VERSION 5.7 ;
  NOWIREEXTENSIONATPIN ON ;
  DIVIDERCHAR "/" ;
  BUSBITCHARS "[]" ;
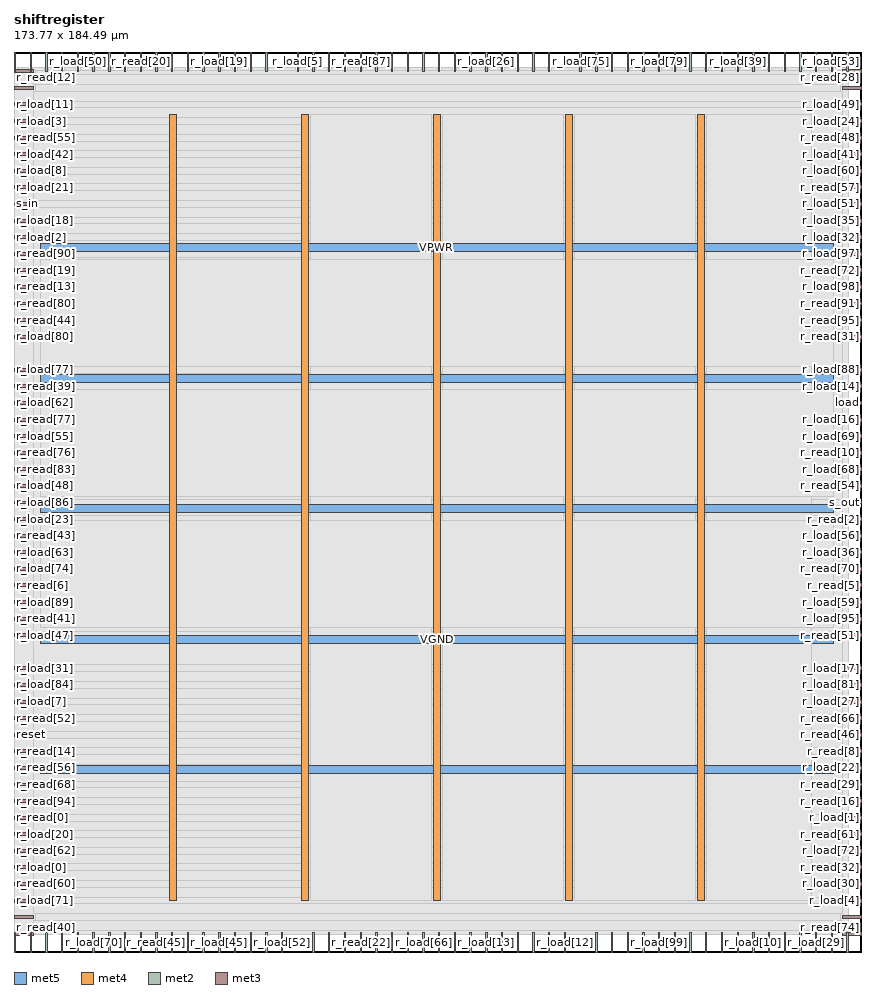
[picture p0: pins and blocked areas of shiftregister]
MACRO shiftregister
  CLASS BLOCK ;
  FOREIGN shiftregister ;
  ORIGIN 0.000 0.000 ;
  SIZE 173.770 BY 184.490 ;
  PIN VGND
    DIRECTION INPUT ;
    USE GROUND ;
    PORT
      LAYER met5 ;
        RECT 5.520 63.335 167.900 64.935 ;
    END
    PORT
      LAYER met5 ;
        RECT 5.520 116.825 167.900 118.425 ;
    END
    PORT
      LAYER met4 ;
        RECT 58.850 10.640 60.450 171.600 ;
    END
    PORT
      LAYER met4 ;
        RECT 112.975 10.640 114.575 171.600 ;
    END
  END VGND
  PIN VPWR
    DIRECTION INPUT ;
    USE POWER ;
    PORT
      LAYER met5 ;
        RECT 5.520 36.585 167.900 38.185 ;
    END
    PORT
      LAYER met5 ;
        RECT 5.520 90.080 167.900 91.680 ;
    END
    PORT
      LAYER met5 ;
        RECT 5.520 143.575 167.900 145.175 ;
    END
    PORT
      LAYER met4 ;
        RECT 31.780 10.640 33.380 171.600 ;
    END
    PORT
      LAYER met4 ;
        RECT 85.910 10.640 87.510 171.600 ;
    END
    PORT
      LAYER met4 ;
        RECT 140.035 10.640 141.635 171.600 ;
    END
  END VPWR
  PIN clk
    DIRECTION INPUT ;
    USE SIGNAL ;
    PORT
      LAYER met2 ;
        RECT 125.670 180.490 125.950 184.490 ;
    END
  END clk
  PIN load
    DIRECTION INPUT ;
    USE SIGNAL ;
    PORT
      LAYER met3 ;
        RECT 169.770 112.240 173.770 112.840 ;
    END
  END load
  PIN r_load[0]
    DIRECTION OUTPUT TRISTATE ;
    USE SIGNAL ;
    PORT
      LAYER met3 ;
        RECT 0.000 17.040 4.000 17.640 ;
    END
  END r_load[0]
  PIN r_load[10]
    DIRECTION OUTPUT TRISTATE ;
    USE SIGNAL ;
    PORT
      LAYER met2 ;
        RECT 151.430 0.000 151.710 4.000 ;
    END
  END r_load[10]
  PIN r_load[11]
    DIRECTION OUTPUT TRISTATE ;
    USE SIGNAL ;
    PORT
      LAYER met3 ;
        RECT 0.000 173.440 4.000 174.040 ;
    END
  END r_load[11]
  PIN r_load[12]
    DIRECTION OUTPUT TRISTATE ;
    USE SIGNAL ;
    PORT
      LAYER met2 ;
        RECT 112.790 0.000 113.070 4.000 ;
    END
  END r_load[12]
  PIN r_load[13]
    DIRECTION OUTPUT TRISTATE ;
    USE SIGNAL ;
    PORT
      LAYER met2 ;
        RECT 96.690 0.000 96.970 4.000 ;
    END
  END r_load[13]
  PIN r_load[14]
    DIRECTION OUTPUT TRISTATE ;
    USE SIGNAL ;
    PORT
      LAYER met3 ;
        RECT 169.770 115.640 173.770 116.240 ;
    END
  END r_load[14]
  PIN r_load[15]
    DIRECTION OUTPUT TRISTATE ;
    USE SIGNAL ;
    PORT
      LAYER met2 ;
        RECT 38.730 180.490 39.010 184.490 ;
    END
  END r_load[15]
  PIN r_load[16]
    DIRECTION OUTPUT TRISTATE ;
    USE SIGNAL ;
    PORT
      LAYER met3 ;
        RECT 169.770 108.840 173.770 109.440 ;
    END
  END r_load[16]
  PIN r_load[17]
    DIRECTION OUTPUT TRISTATE ;
    USE SIGNAL ;
    PORT
      LAYER met3 ;
        RECT 169.770 57.840 173.770 58.440 ;
    END
  END r_load[17]
  PIN r_load[18]
    DIRECTION OUTPUT TRISTATE ;
    USE SIGNAL ;
    PORT
      LAYER met3 ;
        RECT 0.000 149.640 4.000 150.240 ;
    END
  END r_load[18]
  PIN r_load[19]
    DIRECTION OUTPUT TRISTATE ;
    USE SIGNAL ;
    PORT
      LAYER met2 ;
        RECT 41.950 180.490 42.230 184.490 ;
    END
  END r_load[19]
  PIN r_load[1]
    DIRECTION OUTPUT TRISTATE ;
    USE SIGNAL ;
    PORT
      LAYER met3 ;
        RECT 169.770 27.240 173.770 27.840 ;
    END
  END r_load[1]
  PIN r_load[20]
    DIRECTION OUTPUT TRISTATE ;
    USE SIGNAL ;
    PORT
      LAYER met3 ;
        RECT 0.000 23.840 4.000 24.440 ;
    END
  END r_load[20]
  PIN r_load[21]
    DIRECTION OUTPUT TRISTATE ;
    USE SIGNAL ;
    PORT
      LAYER met3 ;
        RECT 0.000 156.440 4.000 157.040 ;
    END
  END r_load[21]
  PIN r_load[22]
    DIRECTION OUTPUT TRISTATE ;
    USE SIGNAL ;
    PORT
      LAYER met3 ;
        RECT 169.770 37.440 173.770 38.040 ;
    END
  END r_load[22]
  PIN r_load[23]
    DIRECTION OUTPUT TRISTATE ;
    USE SIGNAL ;
    PORT
      LAYER met3 ;
        RECT 0.000 88.440 4.000 89.040 ;
    END
  END r_load[23]
  PIN r_load[24]
    DIRECTION OUTPUT TRISTATE ;
    USE SIGNAL ;
    PORT
      LAYER met3 ;
        RECT 169.770 170.040 173.770 170.640 ;
    END
  END r_load[24]
  PIN r_load[25]
    DIRECTION OUTPUT TRISTATE ;
    USE SIGNAL ;
    PORT
      LAYER met2 ;
        RECT 138.550 180.490 138.830 184.490 ;
    END
  END r_load[25]
  PIN r_load[26]
    DIRECTION OUTPUT TRISTATE ;
    USE SIGNAL ;
    PORT
      LAYER met2 ;
        RECT 96.690 180.490 96.970 184.490 ;
    END
  END r_load[26]
  PIN r_load[27]
    DIRECTION OUTPUT TRISTATE ;
    USE SIGNAL ;
    PORT
      LAYER met3 ;
        RECT 169.770 51.040 173.770 51.640 ;
    END
  END r_load[27]
  PIN r_load[28]
    DIRECTION OUTPUT TRISTATE ;
    USE SIGNAL ;
    PORT
      LAYER met2 ;
        RECT 67.710 180.490 67.990 184.490 ;
    END
  END r_load[28]
  PIN r_load[29]
    DIRECTION OUTPUT TRISTATE ;
    USE SIGNAL ;
    PORT
      LAYER met2 ;
        RECT 164.310 0.000 164.590 4.000 ;
    END
  END r_load[29]
  PIN r_load[2]
    DIRECTION OUTPUT TRISTATE ;
    USE SIGNAL ;
    PORT
      LAYER met3 ;
        RECT 0.000 146.240 4.000 146.840 ;
    END
  END r_load[2]
  PIN r_load[30]
    DIRECTION OUTPUT TRISTATE ;
    USE SIGNAL ;
    PORT
      LAYER met3 ;
        RECT 169.770 13.640 173.770 14.240 ;
    END
  END r_load[30]
  PIN r_load[31]
    DIRECTION OUTPUT TRISTATE ;
    USE SIGNAL ;
    PORT
      LAYER met3 ;
        RECT 0.000 57.840 4.000 58.440 ;
    END
  END r_load[31]
  PIN r_load[32]
    DIRECTION OUTPUT TRISTATE ;
    USE SIGNAL ;
    PORT
      LAYER met3 ;
        RECT 169.770 146.240 173.770 146.840 ;
    END
  END r_load[32]
  PIN r_load[33]
    DIRECTION OUTPUT TRISTATE ;
    USE SIGNAL ;
    PORT
      LAYER met2 ;
        RECT 51.610 0.000 51.890 4.000 ;
    END
  END r_load[33]
  PIN r_load[34]
    DIRECTION OUTPUT TRISTATE ;
    USE SIGNAL ;
    PORT
      LAYER met2 ;
        RECT 87.030 0.000 87.310 4.000 ;
    END
  END r_load[34]
  PIN r_load[35]
    DIRECTION OUTPUT TRISTATE ;
    USE SIGNAL ;
    PORT
      LAYER met3 ;
        RECT 169.770 149.640 173.770 150.240 ;
    END
  END r_load[35]
  PIN r_load[36]
    DIRECTION OUTPUT TRISTATE ;
    USE SIGNAL ;
    PORT
      LAYER met3 ;
        RECT 169.770 81.640 173.770 82.240 ;
    END
  END r_load[36]
  PIN r_load[37]
    DIRECTION OUTPUT TRISTATE ;
    USE SIGNAL ;
    PORT
      LAYER met2 ;
        RECT 141.770 0.000 142.050 4.000 ;
    END
  END r_load[37]
  PIN r_load[38]
    DIRECTION OUTPUT TRISTATE ;
    USE SIGNAL ;
    PORT
      LAYER met2 ;
        RECT 122.450 0.000 122.730 4.000 ;
    END
  END r_load[38]
  PIN r_load[39]
    DIRECTION OUTPUT TRISTATE ;
    USE SIGNAL ;
    PORT
      LAYER met2 ;
        RECT 148.210 180.490 148.490 184.490 ;
    END
  END r_load[39]
  PIN r_load[3]
    DIRECTION OUTPUT TRISTATE ;
    USE SIGNAL ;
    PORT
      LAYER met3 ;
        RECT 0.000 170.040 4.000 170.640 ;
    END
  END r_load[3]
  PIN r_load[40]
    DIRECTION OUTPUT TRISTATE ;
    USE SIGNAL ;
    PORT
      LAYER met2 ;
        RECT 35.510 180.490 35.790 184.490 ;
    END
  END r_load[40]
  PIN r_load[41]
    DIRECTION OUTPUT TRISTATE ;
    USE SIGNAL ;
    PORT
      LAYER met3 ;
        RECT 169.770 163.240 173.770 163.840 ;
    END
  END r_load[41]
  PIN r_load[42]
    DIRECTION OUTPUT TRISTATE ;
    USE SIGNAL ;
    PORT
      LAYER met3 ;
        RECT 0.000 163.240 4.000 163.840 ;
    END
  END r_load[42]
  PIN r_load[43]
    DIRECTION OUTPUT TRISTATE ;
    USE SIGNAL ;
    PORT
      LAYER met2 ;
        RECT 48.390 180.490 48.670 184.490 ;
    END
  END r_load[43]
  PIN r_load[44]
    DIRECTION OUTPUT TRISTATE ;
    USE SIGNAL ;
    PORT
      LAYER met2 ;
        RECT 170.750 0.000 171.030 4.000 ;
    END
  END r_load[44]
  PIN r_load[45]
    DIRECTION OUTPUT TRISTATE ;
    USE SIGNAL ;
    PORT
      LAYER met2 ;
        RECT 41.950 0.000 42.230 4.000 ;
    END
  END r_load[45]
  PIN r_load[46]
    DIRECTION OUTPUT TRISTATE ;
    USE SIGNAL ;
    PORT
      LAYER met2 ;
        RECT 157.870 180.490 158.150 184.490 ;
    END
  END r_load[46]
  PIN r_load[47]
    DIRECTION OUTPUT TRISTATE ;
    USE SIGNAL ;
    PORT
      LAYER met3 ;
        RECT 0.000 64.640 4.000 65.240 ;
    END
  END r_load[47]
  PIN r_load[48]
    DIRECTION OUTPUT TRISTATE ;
    USE SIGNAL ;
    PORT
      LAYER met3 ;
        RECT 0.000 95.240 4.000 95.840 ;
    END
  END r_load[48]
  PIN r_load[49]
    DIRECTION OUTPUT TRISTATE ;
    USE SIGNAL ;
    PORT
      LAYER met3 ;
        RECT 169.770 173.440 173.770 174.040 ;
    END
  END r_load[49]
  PIN r_load[4]
    DIRECTION OUTPUT TRISTATE ;
    USE SIGNAL ;
    PORT
      LAYER met3 ;
        RECT 169.770 10.240 173.770 10.840 ;
    END
  END r_load[4]
  PIN r_load[50]
    DIRECTION OUTPUT TRISTATE ;
    USE SIGNAL ;
    PORT
      LAYER met2 ;
        RECT 12.970 180.490 13.250 184.490 ;
    END
  END r_load[50]
  PIN r_load[51]
    DIRECTION OUTPUT TRISTATE ;
    USE SIGNAL ;
    PORT
      LAYER met3 ;
        RECT 169.770 153.040 173.770 153.640 ;
    END
  END r_load[51]
  PIN r_load[52]
    DIRECTION OUTPUT TRISTATE ;
    USE SIGNAL ;
    PORT
      LAYER met2 ;
        RECT 54.830 0.000 55.110 4.000 ;
    END
  END r_load[52]
  PIN r_load[53]
    DIRECTION OUTPUT TRISTATE ;
    USE SIGNAL ;
    PORT
      LAYER met2 ;
        RECT 170.750 180.490 171.030 184.490 ;
    END
  END r_load[53]
  PIN r_load[54]
    DIRECTION OUTPUT TRISTATE ;
    USE SIGNAL ;
    PORT
      LAYER met2 ;
        RECT 161.090 180.490 161.370 184.490 ;
    END
  END r_load[54]
  PIN r_load[55]
    DIRECTION OUTPUT TRISTATE ;
    USE SIGNAL ;
    PORT
      LAYER met3 ;
        RECT 0.000 105.440 4.000 106.040 ;
    END
  END r_load[55]
  PIN r_load[56]
    DIRECTION OUTPUT TRISTATE ;
    USE SIGNAL ;
    PORT
      LAYER met3 ;
        RECT 169.770 85.040 173.770 85.640 ;
    END
  END r_load[56]
  PIN r_load[57]
    DIRECTION OUTPUT TRISTATE ;
    USE SIGNAL ;
    PORT
      LAYER met2 ;
        RECT 144.990 0.000 145.270 4.000 ;
    END
  END r_load[57]
  PIN r_load[58]
    DIRECTION OUTPUT TRISTATE ;
    USE SIGNAL ;
    PORT
      LAYER met2 ;
        RECT 90.250 180.490 90.530 184.490 ;
    END
  END r_load[58]
  PIN r_load[59]
    DIRECTION OUTPUT TRISTATE ;
    USE SIGNAL ;
    PORT
      LAYER met3 ;
        RECT 169.770 71.440 173.770 72.040 ;
    END
  END r_load[59]
  PIN r_load[5]
    DIRECTION OUTPUT TRISTATE ;
    USE SIGNAL ;
    PORT
      LAYER met2 ;
        RECT 58.050 180.490 58.330 184.490 ;
    END
  END r_load[5]
  PIN r_load[60]
    DIRECTION OUTPUT TRISTATE ;
    USE SIGNAL ;
    PORT
      LAYER met3 ;
        RECT 169.770 159.840 173.770 160.440 ;
    END
  END r_load[60]
  PIN r_load[61]
    DIRECTION OUTPUT TRISTATE ;
    USE SIGNAL ;
    PORT
      LAYER met2 ;
        RECT 141.770 180.490 142.050 184.490 ;
    END
  END r_load[61]
  PIN r_load[62]
    DIRECTION OUTPUT TRISTATE ;
    USE SIGNAL ;
    PORT
      LAYER met3 ;
        RECT 0.000 112.240 4.000 112.840 ;
    END
  END r_load[62]
  PIN r_load[63]
    DIRECTION OUTPUT TRISTATE ;
    USE SIGNAL ;
    PORT
      LAYER met3 ;
        RECT 0.000 81.640 4.000 82.240 ;
    END
  END r_load[63]
  PIN r_load[64]
    DIRECTION OUTPUT TRISTATE ;
    USE SIGNAL ;
    PORT
      LAYER met2 ;
        RECT 32.290 180.490 32.570 184.490 ;
    END
  END r_load[64]
  PIN r_load[65]
    DIRECTION OUTPUT TRISTATE ;
    USE SIGNAL ;
    PORT
      LAYER met2 ;
        RECT 77.370 180.490 77.650 184.490 ;
    END
  END r_load[65]
  PIN r_load[66]
    DIRECTION OUTPUT TRISTATE ;
    USE SIGNAL ;
    PORT
      LAYER met2 ;
        RECT 83.810 0.000 84.090 4.000 ;
    END
  END r_load[66]
  PIN r_load[67]
    DIRECTION OUTPUT TRISTATE ;
    USE SIGNAL ;
    PORT
      LAYER met2 ;
        RECT 167.530 0.000 167.810 4.000 ;
    END
  END r_load[67]
  PIN r_load[68]
    DIRECTION OUTPUT TRISTATE ;
    USE SIGNAL ;
    PORT
      LAYER met3 ;
        RECT 169.770 98.640 173.770 99.240 ;
    END
  END r_load[68]
  PIN r_load[69]
    DIRECTION OUTPUT TRISTATE ;
    USE SIGNAL ;
    PORT
      LAYER met3 ;
        RECT 169.770 105.440 173.770 106.040 ;
    END
  END r_load[69]
  PIN r_load[6]
    DIRECTION OUTPUT TRISTATE ;
    USE SIGNAL ;
    PORT
      LAYER met2 ;
        RECT 45.170 180.490 45.450 184.490 ;
    END
  END r_load[6]
  PIN r_load[70]
    DIRECTION OUTPUT TRISTATE ;
    USE SIGNAL ;
    PORT
      LAYER met2 ;
        RECT 16.190 0.000 16.470 4.000 ;
    END
  END r_load[70]
  PIN r_load[71]
    DIRECTION OUTPUT TRISTATE ;
    USE SIGNAL ;
    PORT
      LAYER met3 ;
        RECT 0.000 10.240 4.000 10.840 ;
    END
  END r_load[71]
  PIN r_load[72]
    DIRECTION OUTPUT TRISTATE ;
    USE SIGNAL ;
    PORT
      LAYER met3 ;
        RECT 169.770 20.440 173.770 21.040 ;
    END
  END r_load[72]
  PIN r_load[73]
    DIRECTION OUTPUT TRISTATE ;
    USE SIGNAL ;
    PORT
      LAYER met2 ;
        RECT 61.270 180.490 61.550 184.490 ;
    END
  END r_load[73]
  PIN r_load[74]
    DIRECTION OUTPUT TRISTATE ;
    USE SIGNAL ;
    PORT
      LAYER met3 ;
        RECT 0.000 78.240 4.000 78.840 ;
    END
  END r_load[74]
  PIN r_load[75]
    DIRECTION OUTPUT TRISTATE ;
    USE SIGNAL ;
    PORT
      LAYER met2 ;
        RECT 116.010 180.490 116.290 184.490 ;
    END
  END r_load[75]
  PIN r_load[76]
    DIRECTION OUTPUT TRISTATE ;
    USE SIGNAL ;
    PORT
      LAYER met2 ;
        RECT 138.550 0.000 138.830 4.000 ;
    END
  END r_load[76]
  PIN r_load[77]
    DIRECTION OUTPUT TRISTATE ;
    USE SIGNAL ;
    PORT
      LAYER met3 ;
        RECT 0.000 119.040 4.000 119.640 ;
    END
  END r_load[77]
  PIN r_load[78]
    DIRECTION OUTPUT TRISTATE ;
    USE SIGNAL ;
    PORT
      LAYER met2 ;
        RECT 128.890 180.490 129.170 184.490 ;
    END
  END r_load[78]
  PIN r_load[79]
    DIRECTION OUTPUT TRISTATE ;
    USE SIGNAL ;
    PORT
      LAYER met2 ;
        RECT 132.110 180.490 132.390 184.490 ;
    END
  END r_load[79]
  PIN r_load[7]
    DIRECTION OUTPUT TRISTATE ;
    USE SIGNAL ;
    PORT
      LAYER met3 ;
        RECT 0.000 51.040 4.000 51.640 ;
    END
  END r_load[7]
  PIN r_load[80]
    DIRECTION OUTPUT TRISTATE ;
    USE SIGNAL ;
    PORT
      LAYER met3 ;
        RECT 0.000 125.840 4.000 126.440 ;
    END
  END r_load[80]
  PIN r_load[81]
    DIRECTION OUTPUT TRISTATE ;
    USE SIGNAL ;
    PORT
      LAYER met3 ;
        RECT 169.770 54.440 173.770 55.040 ;
    END
  END r_load[81]
  PIN r_load[82]
    DIRECTION OUTPUT TRISTATE ;
    USE SIGNAL ;
    PORT
      LAYER met2 ;
        RECT 148.210 0.000 148.490 4.000 ;
    END
  END r_load[82]
  PIN r_load[83]
    DIRECTION OUTPUT TRISTATE ;
    USE SIGNAL ;
    PORT
      LAYER met3 ;
        RECT 0.000 6.840 4.000 7.440 ;
    END
  END r_load[83]
  PIN r_load[84]
    DIRECTION OUTPUT TRISTATE ;
    USE SIGNAL ;
    PORT
      LAYER met3 ;
        RECT 0.000 54.440 4.000 55.040 ;
    END
  END r_load[84]
  PIN r_load[85]
    DIRECTION OUTPUT TRISTATE ;
    USE SIGNAL ;
    PORT
      LAYER met2 ;
        RECT 109.570 0.000 109.850 4.000 ;
    END
  END r_load[85]
  PIN r_load[86]
    DIRECTION OUTPUT TRISTATE ;
    USE SIGNAL ;
    PORT
      LAYER met3 ;
        RECT 0.000 91.840 4.000 92.440 ;
    END
  END r_load[86]
  PIN r_load[87]
    DIRECTION OUTPUT TRISTATE ;
    USE SIGNAL ;
    PORT
      LAYER met2 ;
        RECT 93.470 0.000 93.750 4.000 ;
    END
  END r_load[87]
  PIN r_load[88]
    DIRECTION OUTPUT TRISTATE ;
    USE SIGNAL ;
    PORT
      LAYER met3 ;
        RECT 169.770 119.040 173.770 119.640 ;
    END
  END r_load[88]
  PIN r_load[89]
    DIRECTION OUTPUT TRISTATE ;
    USE SIGNAL ;
    PORT
      LAYER met3 ;
        RECT 0.000 71.440 4.000 72.040 ;
    END
  END r_load[89]
  PIN r_load[8]
    DIRECTION OUTPUT TRISTATE ;
    USE SIGNAL ;
    PORT
      LAYER met3 ;
        RECT 0.000 159.840 4.000 160.440 ;
    END
  END r_load[8]
  PIN r_load[90]
    DIRECTION OUTPUT TRISTATE ;
    USE SIGNAL ;
    PORT
      LAYER met2 ;
        RECT 61.270 0.000 61.550 4.000 ;
    END
  END r_load[90]
  PIN r_load[91]
    DIRECTION OUTPUT TRISTATE ;
    USE SIGNAL ;
    PORT
      LAYER met3 ;
        RECT 169.770 6.840 173.770 7.440 ;
    END
  END r_load[91]
  PIN r_load[92]
    DIRECTION OUTPUT TRISTATE ;
    USE SIGNAL ;
    PORT
      LAYER met2 ;
        RECT 25.850 0.000 26.130 4.000 ;
    END
  END r_load[92]
  PIN r_load[93]
    DIRECTION OUTPUT TRISTATE ;
    USE SIGNAL ;
    PORT
      LAYER met2 ;
        RECT 87.030 180.490 87.310 184.490 ;
    END
  END r_load[93]
  PIN r_load[94]
    DIRECTION OUTPUT TRISTATE ;
    USE SIGNAL ;
    PORT
      LAYER met2 ;
        RECT 167.530 180.490 167.810 184.490 ;
    END
  END r_load[94]
  PIN r_load[95]
    DIRECTION OUTPUT TRISTATE ;
    USE SIGNAL ;
    PORT
      LAYER met3 ;
        RECT 169.770 68.040 173.770 68.640 ;
    END
  END r_load[95]
  PIN r_load[96]
    DIRECTION OUTPUT TRISTATE ;
    USE SIGNAL ;
    PORT
      LAYER met2 ;
        RECT 144.990 180.490 145.270 184.490 ;
    END
  END r_load[96]
  PIN r_load[97]
    DIRECTION OUTPUT TRISTATE ;
    USE SIGNAL ;
    PORT
      LAYER met3 ;
        RECT 169.770 142.840 173.770 143.440 ;
    END
  END r_load[97]
  PIN r_load[98]
    DIRECTION OUTPUT TRISTATE ;
    USE SIGNAL ;
    PORT
      LAYER met3 ;
        RECT 169.770 136.040 173.770 136.640 ;
    END
  END r_load[98]
  PIN r_load[99]
    DIRECTION OUTPUT TRISTATE ;
    USE SIGNAL ;
    PORT
      LAYER met2 ;
        RECT 132.110 0.000 132.390 4.000 ;
    END
  END r_load[99]
  PIN r_load[9]
    DIRECTION OUTPUT TRISTATE ;
    USE SIGNAL ;
    PORT
      LAYER met2 ;
        RECT 0.090 180.490 0.370 184.490 ;
    END
  END r_load[9]
  PIN r_read[0]
    DIRECTION INPUT ;
    USE SIGNAL ;
    PORT
      LAYER met3 ;
        RECT 0.000 27.240 4.000 27.840 ;
    END
  END r_read[0]
  PIN r_read[10]
    DIRECTION INPUT ;
    USE SIGNAL ;
    PORT
      LAYER met3 ;
        RECT 169.770 102.040 173.770 102.640 ;
    END
  END r_read[10]
  PIN r_read[11]
    DIRECTION INPUT ;
    USE SIGNAL ;
    PORT
      LAYER met2 ;
        RECT 83.810 180.490 84.090 184.490 ;
    END
  END r_read[11]
  PIN r_read[12]
    DIRECTION INPUT ;
    USE SIGNAL ;
    PORT
      LAYER met3 ;
        RECT 0.000 180.240 4.000 180.840 ;
    END
  END r_read[12]
  PIN r_read[13]
    DIRECTION INPUT ;
    USE SIGNAL ;
    PORT
      LAYER met3 ;
        RECT 0.000 136.040 4.000 136.640 ;
    END
  END r_read[13]
  PIN r_read[14]
    DIRECTION INPUT ;
    USE SIGNAL ;
    PORT
      LAYER met3 ;
        RECT 0.000 40.840 4.000 41.440 ;
    END
  END r_read[14]
  PIN r_read[15]
    DIRECTION INPUT ;
    USE SIGNAL ;
    PORT
      LAYER met2 ;
        RECT 103.130 180.490 103.410 184.490 ;
    END
  END r_read[15]
  PIN r_read[16]
    DIRECTION INPUT ;
    USE SIGNAL ;
    PORT
      LAYER met3 ;
        RECT 169.770 30.640 173.770 31.240 ;
    END
  END r_read[16]
  PIN r_read[17]
    DIRECTION INPUT ;
    USE SIGNAL ;
    PORT
      LAYER met2 ;
        RECT 77.370 0.000 77.650 4.000 ;
    END
  END r_read[17]
  PIN r_read[18]
    DIRECTION INPUT ;
    USE SIGNAL ;
    PORT
      LAYER met2 ;
        RECT 6.530 180.490 6.810 184.490 ;
    END
  END r_read[18]
  PIN r_read[19]
    DIRECTION INPUT ;
    USE SIGNAL ;
    PORT
      LAYER met3 ;
        RECT 0.000 139.440 4.000 140.040 ;
    END
  END r_read[19]
  PIN r_read[1]
    DIRECTION INPUT ;
    USE SIGNAL ;
    PORT
      LAYER met2 ;
        RECT 119.230 0.000 119.510 4.000 ;
    END
  END r_read[1]
  PIN r_read[20]
    DIRECTION INPUT ;
    USE SIGNAL ;
    PORT
      LAYER met2 ;
        RECT 25.850 180.490 26.130 184.490 ;
    END
  END r_read[20]
  PIN r_read[21]
    DIRECTION INPUT ;
    USE SIGNAL ;
    PORT
      LAYER met2 ;
        RECT 99.910 180.490 100.190 184.490 ;
    END
  END r_read[21]
  PIN r_read[22]
    DIRECTION INPUT ;
    USE SIGNAL ;
    PORT
      LAYER met2 ;
        RECT 70.930 0.000 71.210 4.000 ;
    END
  END r_read[22]
  PIN r_read[23]
    DIRECTION INPUT ;
    USE SIGNAL ;
    PORT
      LAYER met2 ;
        RECT 51.610 180.490 51.890 184.490 ;
    END
  END r_read[23]
  PIN r_read[24]
    DIRECTION INPUT ;
    USE SIGNAL ;
    PORT
      LAYER met2 ;
        RECT 154.650 0.000 154.930 4.000 ;
    END
  END r_read[24]
  PIN r_read[25]
    DIRECTION INPUT ;
    USE SIGNAL ;
    PORT
      LAYER met2 ;
        RECT 64.490 180.490 64.770 184.490 ;
    END
  END r_read[25]
  PIN r_read[26]
    DIRECTION INPUT ;
    USE SIGNAL ;
    PORT
      LAYER met2 ;
        RECT 67.710 0.000 67.990 4.000 ;
    END
  END r_read[26]
  PIN r_read[27]
    DIRECTION INPUT ;
    USE SIGNAL ;
    PORT
      LAYER met2 ;
        RECT 12.970 0.000 13.250 4.000 ;
    END
  END r_read[27]
  PIN r_read[28]
    DIRECTION INPUT ;
    USE SIGNAL ;
    PORT
      LAYER met3 ;
        RECT 169.770 180.240 173.770 180.840 ;
    END
  END r_read[28]
  PIN r_read[29]
    DIRECTION INPUT ;
    USE SIGNAL ;
    PORT
      LAYER met3 ;
        RECT 169.770 34.040 173.770 34.640 ;
    END
  END r_read[29]
  PIN r_read[2]
    DIRECTION INPUT ;
    USE SIGNAL ;
    PORT
      LAYER met3 ;
        RECT 169.770 88.440 173.770 89.040 ;
    END
  END r_read[2]
  PIN r_read[30]
    DIRECTION INPUT ;
    USE SIGNAL ;
    PORT
      LAYER met2 ;
        RECT 48.390 0.000 48.670 4.000 ;
    END
  END r_read[30]
  PIN r_read[31]
    DIRECTION INPUT ;
    USE SIGNAL ;
    PORT
      LAYER met3 ;
        RECT 169.770 125.840 173.770 126.440 ;
    END
  END r_read[31]
  PIN r_read[32]
    DIRECTION INPUT ;
    USE SIGNAL ;
    PORT
      LAYER met3 ;
        RECT 169.770 17.040 173.770 17.640 ;
    END
  END r_read[32]
  PIN r_read[33]
    DIRECTION INPUT ;
    USE SIGNAL ;
    PORT
      LAYER met2 ;
        RECT 103.130 0.000 103.410 4.000 ;
    END
  END r_read[33]
  PIN r_read[34]
    DIRECTION INPUT ;
    USE SIGNAL ;
    PORT
      LAYER met2 ;
        RECT 29.070 180.490 29.350 184.490 ;
    END
  END r_read[34]
  PIN r_read[35]
    DIRECTION INPUT ;
    USE SIGNAL ;
    PORT
      LAYER met2 ;
        RECT 3.310 180.490 3.590 184.490 ;
    END
  END r_read[35]
  PIN r_read[36]
    DIRECTION INPUT ;
    USE SIGNAL ;
    PORT
      LAYER met2 ;
        RECT 38.730 0.000 39.010 4.000 ;
    END
  END r_read[36]
  PIN r_read[37]
    DIRECTION INPUT ;
    USE SIGNAL ;
    PORT
      LAYER met2 ;
        RECT 6.530 0.000 6.810 4.000 ;
    END
  END r_read[37]
  PIN r_read[38]
    DIRECTION INPUT ;
    USE SIGNAL ;
    PORT
      LAYER met2 ;
        RECT 135.330 0.000 135.610 4.000 ;
    END
  END r_read[38]
  PIN r_read[39]
    DIRECTION INPUT ;
    USE SIGNAL ;
    PORT
      LAYER met3 ;
        RECT 0.000 115.640 4.000 116.240 ;
    END
  END r_read[39]
  PIN r_read[3]
    DIRECTION INPUT ;
    USE SIGNAL ;
    PORT
      LAYER met2 ;
        RECT 151.430 180.490 151.710 184.490 ;
    END
  END r_read[3]
  PIN r_read[40]
    DIRECTION INPUT ;
    USE SIGNAL ;
    PORT
      LAYER met3 ;
        RECT 0.000 3.440 4.000 4.040 ;
    END
  END r_read[40]
  PIN r_read[41]
    DIRECTION INPUT ;
    USE SIGNAL ;
    PORT
      LAYER met3 ;
        RECT 0.000 68.040 4.000 68.640 ;
    END
  END r_read[41]
  PIN r_read[42]
    DIRECTION INPUT ;
    USE SIGNAL ;
    PORT
      LAYER met2 ;
        RECT 80.590 180.490 80.870 184.490 ;
    END
  END r_read[42]
  PIN r_read[43]
    DIRECTION INPUT ;
    USE SIGNAL ;
    PORT
      LAYER met3 ;
        RECT 0.000 85.040 4.000 85.640 ;
    END
  END r_read[43]
  PIN r_read[44]
    DIRECTION INPUT ;
    USE SIGNAL ;
    PORT
      LAYER met3 ;
        RECT 0.000 129.240 4.000 129.840 ;
    END
  END r_read[44]
  PIN r_read[45]
    DIRECTION INPUT ;
    USE SIGNAL ;
    PORT
      LAYER met2 ;
        RECT 29.070 0.000 29.350 4.000 ;
    END
  END r_read[45]
  PIN r_read[46]
    DIRECTION INPUT ;
    USE SIGNAL ;
    PORT
      LAYER met3 ;
        RECT 169.770 44.240 173.770 44.840 ;
    END
  END r_read[46]
  PIN r_read[47]
    DIRECTION INPUT ;
    USE SIGNAL ;
    PORT
      LAYER met2 ;
        RECT 80.590 0.000 80.870 4.000 ;
    END
  END r_read[47]
  PIN r_read[48]
    DIRECTION INPUT ;
    USE SIGNAL ;
    PORT
      LAYER met3 ;
        RECT 169.770 166.640 173.770 167.240 ;
    END
  END r_read[48]
  PIN r_read[49]
    DIRECTION INPUT ;
    USE SIGNAL ;
    PORT
      LAYER met2 ;
        RECT 16.190 180.490 16.470 184.490 ;
    END
  END r_read[49]
  PIN r_read[4]
    DIRECTION INPUT ;
    USE SIGNAL ;
    PORT
      LAYER met2 ;
        RECT 93.470 180.490 93.750 184.490 ;
    END
  END r_read[4]
  PIN r_read[50]
    DIRECTION INPUT ;
    USE SIGNAL ;
    PORT
      LAYER met2 ;
        RECT 19.410 0.000 19.690 4.000 ;
    END
  END r_read[50]
  PIN r_read[51]
    DIRECTION INPUT ;
    USE SIGNAL ;
    PORT
      LAYER met3 ;
        RECT 169.770 64.640 173.770 65.240 ;
    END
  END r_read[51]
  PIN r_read[52]
    DIRECTION INPUT ;
    USE SIGNAL ;
    PORT
      LAYER met3 ;
        RECT 0.000 47.640 4.000 48.240 ;
    END
  END r_read[52]
  PIN r_read[53]
    DIRECTION INPUT ;
    USE SIGNAL ;
    PORT
      LAYER met2 ;
        RECT 19.410 180.490 19.690 184.490 ;
    END
  END r_read[53]
  PIN r_read[54]
    DIRECTION INPUT ;
    USE SIGNAL ;
    PORT
      LAYER met3 ;
        RECT 169.770 95.240 173.770 95.840 ;
    END
  END r_read[54]
  PIN r_read[55]
    DIRECTION INPUT ;
    USE SIGNAL ;
    PORT
      LAYER met3 ;
        RECT 0.000 166.640 4.000 167.240 ;
    END
  END r_read[55]
  PIN r_read[56]
    DIRECTION INPUT ;
    USE SIGNAL ;
    PORT
      LAYER met3 ;
        RECT 0.000 37.440 4.000 38.040 ;
    END
  END r_read[56]
  PIN r_read[57]
    DIRECTION INPUT ;
    USE SIGNAL ;
    PORT
      LAYER met3 ;
        RECT 169.770 156.440 173.770 157.040 ;
    END
  END r_read[57]
  PIN r_read[58]
    DIRECTION INPUT ;
    USE SIGNAL ;
    PORT
      LAYER met2 ;
        RECT 106.350 180.490 106.630 184.490 ;
    END
  END r_read[58]
  PIN r_read[59]
    DIRECTION INPUT ;
    USE SIGNAL ;
    PORT
      LAYER met2 ;
        RECT 45.170 0.000 45.450 4.000 ;
    END
  END r_read[59]
  PIN r_read[5]
    DIRECTION INPUT ;
    USE SIGNAL ;
    PORT
      LAYER met3 ;
        RECT 169.770 74.840 173.770 75.440 ;
    END
  END r_read[5]
  PIN r_read[60]
    DIRECTION INPUT ;
    USE SIGNAL ;
    PORT
      LAYER met3 ;
        RECT 0.000 13.640 4.000 14.240 ;
    END
  END r_read[60]
  PIN r_read[61]
    DIRECTION INPUT ;
    USE SIGNAL ;
    PORT
      LAYER met3 ;
        RECT 169.770 23.840 173.770 24.440 ;
    END
  END r_read[61]
  PIN r_read[62]
    DIRECTION INPUT ;
    USE SIGNAL ;
    PORT
      LAYER met3 ;
        RECT 0.000 20.440 4.000 21.040 ;
    END
  END r_read[62]
  PIN r_read[63]
    DIRECTION INPUT ;
    USE SIGNAL ;
    PORT
      LAYER met2 ;
        RECT 157.870 0.000 158.150 4.000 ;
    END
  END r_read[63]
  PIN r_read[64]
    DIRECTION INPUT ;
    USE SIGNAL ;
    PORT
      LAYER met2 ;
        RECT 22.630 0.000 22.910 4.000 ;
    END
  END r_read[64]
  PIN r_read[65]
    DIRECTION INPUT ;
    USE SIGNAL ;
    PORT
      LAYER met2 ;
        RECT 74.150 0.000 74.430 4.000 ;
    END
  END r_read[65]
  PIN r_read[66]
    DIRECTION INPUT ;
    USE SIGNAL ;
    PORT
      LAYER met3 ;
        RECT 169.770 47.640 173.770 48.240 ;
    END
  END r_read[66]
  PIN r_read[67]
    DIRECTION INPUT ;
    USE SIGNAL ;
    PORT
      LAYER met3 ;
        RECT 169.770 176.840 173.770 177.440 ;
    END
  END r_read[67]
  PIN r_read[68]
    DIRECTION INPUT ;
    USE SIGNAL ;
    PORT
      LAYER met3 ;
        RECT 0.000 34.040 4.000 34.640 ;
    END
  END r_read[68]
  PIN r_read[69]
    DIRECTION INPUT ;
    USE SIGNAL ;
    PORT
      LAYER met2 ;
        RECT 161.090 0.000 161.370 4.000 ;
    END
  END r_read[69]
  PIN r_read[6]
    DIRECTION INPUT ;
    USE SIGNAL ;
    PORT
      LAYER met3 ;
        RECT 0.000 74.840 4.000 75.440 ;
    END
  END r_read[6]
  PIN r_read[70]
    DIRECTION INPUT ;
    USE SIGNAL ;
    PORT
      LAYER met3 ;
        RECT 169.770 78.240 173.770 78.840 ;
    END
  END r_read[70]
  PIN r_read[71]
    DIRECTION INPUT ;
    USE SIGNAL ;
    PORT
      LAYER met2 ;
        RECT 3.310 0.000 3.590 4.000 ;
    END
  END r_read[71]
  PIN r_read[72]
    DIRECTION INPUT ;
    USE SIGNAL ;
    PORT
      LAYER met3 ;
        RECT 169.770 139.440 173.770 140.040 ;
    END
  END r_read[72]
  PIN r_read[73]
    DIRECTION INPUT ;
    USE SIGNAL ;
    PORT
      LAYER met2 ;
        RECT 164.310 180.490 164.590 184.490 ;
    END
  END r_read[73]
  PIN r_read[74]
    DIRECTION INPUT ;
    USE SIGNAL ;
    PORT
      LAYER met3 ;
        RECT 169.770 3.440 173.770 4.040 ;
    END
  END r_read[74]
  PIN r_read[75]
    DIRECTION INPUT ;
    USE SIGNAL ;
    PORT
      LAYER met2 ;
        RECT 154.650 180.490 154.930 184.490 ;
    END
  END r_read[75]
  PIN r_read[76]
    DIRECTION INPUT ;
    USE SIGNAL ;
    PORT
      LAYER met3 ;
        RECT 0.000 102.040 4.000 102.640 ;
    END
  END r_read[76]
  PIN r_read[77]
    DIRECTION INPUT ;
    USE SIGNAL ;
    PORT
      LAYER met3 ;
        RECT 0.000 108.840 4.000 109.440 ;
    END
  END r_read[77]
  PIN r_read[78]
    DIRECTION INPUT ;
    USE SIGNAL ;
    PORT
      LAYER met2 ;
        RECT 106.350 0.000 106.630 4.000 ;
    END
  END r_read[78]
  PIN r_read[79]
    DIRECTION INPUT ;
    USE SIGNAL ;
    PORT
      LAYER met2 ;
        RECT 0.090 0.000 0.370 4.000 ;
    END
  END r_read[79]
  PIN r_read[7]
    DIRECTION INPUT ;
    USE SIGNAL ;
    PORT
      LAYER met2 ;
        RECT 128.890 0.000 129.170 4.000 ;
    END
  END r_read[7]
  PIN r_read[80]
    DIRECTION INPUT ;
    USE SIGNAL ;
    PORT
      LAYER met3 ;
        RECT 0.000 132.640 4.000 133.240 ;
    END
  END r_read[80]
  PIN r_read[81]
    DIRECTION INPUT ;
    USE SIGNAL ;
    PORT
      LAYER met2 ;
        RECT 9.750 180.490 10.030 184.490 ;
    END
  END r_read[81]
  PIN r_read[82]
    DIRECTION INPUT ;
    USE SIGNAL ;
    PORT
      LAYER met2 ;
        RECT 74.150 180.490 74.430 184.490 ;
    END
  END r_read[82]
  PIN r_read[83]
    DIRECTION INPUT ;
    USE SIGNAL ;
    PORT
      LAYER met3 ;
        RECT 0.000 98.640 4.000 99.240 ;
    END
  END r_read[83]
  PIN r_read[84]
    DIRECTION INPUT ;
    USE SIGNAL ;
    PORT
      LAYER met2 ;
        RECT 32.290 0.000 32.570 4.000 ;
    END
  END r_read[84]
  PIN r_read[85]
    DIRECTION INPUT ;
    USE SIGNAL ;
    PORT
      LAYER met2 ;
        RECT 9.750 0.000 10.030 4.000 ;
    END
  END r_read[85]
  PIN r_read[86]
    DIRECTION INPUT ;
    USE SIGNAL ;
    PORT
      LAYER met2 ;
        RECT 109.570 180.490 109.850 184.490 ;
    END
  END r_read[86]
  PIN r_read[87]
    DIRECTION INPUT ;
    USE SIGNAL ;
    PORT
      LAYER met2 ;
        RECT 70.930 180.490 71.210 184.490 ;
    END
  END r_read[87]
  PIN r_read[88]
    DIRECTION INPUT ;
    USE SIGNAL ;
    PORT
      LAYER met2 ;
        RECT 90.250 0.000 90.530 4.000 ;
    END
  END r_read[88]
  PIN r_read[89]
    DIRECTION INPUT ;
    USE SIGNAL ;
    PORT
      LAYER met2 ;
        RECT 135.330 180.490 135.610 184.490 ;
    END
  END r_read[89]
  PIN r_read[8]
    DIRECTION INPUT ;
    USE SIGNAL ;
    PORT
      LAYER met3 ;
        RECT 169.770 40.840 173.770 41.440 ;
    END
  END r_read[8]
  PIN r_read[90]
    DIRECTION INPUT ;
    USE SIGNAL ;
    PORT
      LAYER met3 ;
        RECT 0.000 142.840 4.000 143.440 ;
    END
  END r_read[90]
  PIN r_read[91]
    DIRECTION INPUT ;
    USE SIGNAL ;
    PORT
      LAYER met3 ;
        RECT 169.770 132.640 173.770 133.240 ;
    END
  END r_read[91]
  PIN r_read[92]
    DIRECTION INPUT ;
    USE SIGNAL ;
    PORT
      LAYER met2 ;
        RECT 35.510 0.000 35.790 4.000 ;
    END
  END r_read[92]
  PIN r_read[93]
    DIRECTION INPUT ;
    USE SIGNAL ;
    PORT
      LAYER met2 ;
        RECT 64.490 0.000 64.770 4.000 ;
    END
  END r_read[93]
  PIN r_read[94]
    DIRECTION INPUT ;
    USE SIGNAL ;
    PORT
      LAYER met3 ;
        RECT 0.000 30.640 4.000 31.240 ;
    END
  END r_read[94]
  PIN r_read[95]
    DIRECTION INPUT ;
    USE SIGNAL ;
    PORT
      LAYER met3 ;
        RECT 169.770 129.240 173.770 129.840 ;
    END
  END r_read[95]
  PIN r_read[96]
    DIRECTION INPUT ;
    USE SIGNAL ;
    PORT
      LAYER met2 ;
        RECT 99.910 0.000 100.190 4.000 ;
    END
  END r_read[96]
  PIN r_read[97]
    DIRECTION INPUT ;
    USE SIGNAL ;
    PORT
      LAYER met2 ;
        RECT 122.450 180.490 122.730 184.490 ;
    END
  END r_read[97]
  PIN r_read[98]
    DIRECTION INPUT ;
    USE SIGNAL ;
    PORT
      LAYER met2 ;
        RECT 119.230 180.490 119.510 184.490 ;
    END
  END r_read[98]
  PIN r_read[99]
    DIRECTION INPUT ;
    USE SIGNAL ;
    PORT
      LAYER met3 ;
        RECT 0.000 176.840 4.000 177.440 ;
    END
  END r_read[99]
  PIN r_read[9]
    DIRECTION INPUT ;
    USE SIGNAL ;
    PORT
      LAYER met2 ;
        RECT 22.630 180.490 22.910 184.490 ;
    END
  END r_read[9]
  PIN read
    DIRECTION INPUT ;
    USE SIGNAL ;
    PORT
      LAYER met2 ;
        RECT 125.670 0.000 125.950 4.000 ;
    END
  END read
  PIN reset
    DIRECTION INPUT ;
    USE SIGNAL ;
    PORT
      LAYER met3 ;
        RECT 0.000 44.240 4.000 44.840 ;
    END
  END reset
  PIN s_in
    DIRECTION INPUT ;
    USE SIGNAL ;
    PORT
      LAYER met3 ;
        RECT 0.000 153.040 4.000 153.640 ;
    END
  END s_in
  PIN s_out
    DIRECTION OUTPUT TRISTATE ;
    USE SIGNAL ;
    PORT
      LAYER met3 ;
        RECT 169.770 91.840 173.770 92.440 ;
    END
  END s_out
  OBS
      LAYER li1 ;
        RECT 5.520 10.795 167.900 171.445 ;
      LAYER met1 ;
        RECT 0.070 7.860 171.050 172.340 ;
      LAYER met2 ;
        RECT 0.650 180.210 3.030 181.290 ;
        RECT 3.870 180.210 6.250 181.290 ;
        RECT 7.090 180.210 9.470 181.290 ;
        RECT 10.310 180.210 12.690 181.290 ;
        RECT 13.530 180.210 15.910 181.290 ;
        RECT 16.750 180.210 19.130 181.290 ;
        RECT 19.970 180.210 22.350 181.290 ;
        RECT 23.190 180.210 25.570 181.290 ;
        RECT 26.410 180.210 28.790 181.290 ;
        RECT 29.630 180.210 32.010 181.290 ;
        RECT 32.850 180.210 35.230 181.290 ;
        RECT 36.070 180.210 38.450 181.290 ;
        RECT 39.290 180.210 41.670 181.290 ;
        RECT 42.510 180.210 44.890 181.290 ;
        RECT 45.730 180.210 48.110 181.290 ;
        RECT 48.950 180.210 51.330 181.290 ;
        RECT 52.170 180.210 57.770 181.290 ;
        RECT 58.610 180.210 60.990 181.290 ;
        RECT 61.830 180.210 64.210 181.290 ;
        RECT 65.050 180.210 67.430 181.290 ;
        RECT 68.270 180.210 70.650 181.290 ;
        RECT 71.490 180.210 73.870 181.290 ;
        RECT 74.710 180.210 77.090 181.290 ;
        RECT 77.930 180.210 80.310 181.290 ;
        RECT 81.150 180.210 83.530 181.290 ;
        RECT 84.370 180.210 86.750 181.290 ;
        RECT 87.590 180.210 89.970 181.290 ;
        RECT 90.810 180.210 93.190 181.290 ;
        RECT 94.030 180.210 96.410 181.290 ;
        RECT 97.250 180.210 99.630 181.290 ;
        RECT 100.470 180.210 102.850 181.290 ;
        RECT 103.690 180.210 106.070 181.290 ;
        RECT 106.910 180.210 109.290 181.290 ;
        RECT 110.130 180.210 115.730 181.290 ;
        RECT 116.570 180.210 118.950 181.290 ;
        RECT 119.790 180.210 122.170 181.290 ;
        RECT 123.010 180.210 125.390 181.290 ;
        RECT 126.230 180.210 128.610 181.290 ;
        RECT 129.450 180.210 131.830 181.290 ;
        RECT 132.670 180.210 135.050 181.290 ;
        RECT 135.890 180.210 138.270 181.290 ;
        RECT 139.110 180.210 141.490 181.290 ;
        RECT 142.330 180.210 144.710 181.290 ;
        RECT 145.550 180.210 147.930 181.290 ;
        RECT 148.770 180.210 151.150 181.290 ;
        RECT 151.990 180.210 154.370 181.290 ;
        RECT 155.210 180.210 157.590 181.290 ;
        RECT 158.430 180.210 160.810 181.290 ;
        RECT 161.650 180.210 164.030 181.290 ;
        RECT 164.870 180.210 167.250 181.290 ;
        RECT 168.090 180.210 170.470 181.290 ;
        RECT 0.100 4.280 171.020 180.210 ;
        RECT 0.650 3.555 3.030 4.280 ;
        RECT 3.870 3.555 6.250 4.280 ;
        RECT 7.090 3.555 9.470 4.280 ;
        RECT 10.310 3.555 12.690 4.280 ;
        RECT 13.530 3.555 15.910 4.280 ;
        RECT 16.750 3.555 19.130 4.280 ;
        RECT 19.970 3.555 22.350 4.280 ;
        RECT 23.190 3.555 25.570 4.280 ;
        RECT 26.410 3.555 28.790 4.280 ;
        RECT 29.630 3.555 32.010 4.280 ;
        RECT 32.850 3.555 35.230 4.280 ;
        RECT 36.070 3.555 38.450 4.280 ;
        RECT 39.290 3.555 41.670 4.280 ;
        RECT 42.510 3.555 44.890 4.280 ;
        RECT 45.730 3.555 48.110 4.280 ;
        RECT 48.950 3.555 51.330 4.280 ;
        RECT 52.170 3.555 54.550 4.280 ;
        RECT 55.390 3.555 60.990 4.280 ;
        RECT 61.830 3.555 64.210 4.280 ;
        RECT 65.050 3.555 67.430 4.280 ;
        RECT 68.270 3.555 70.650 4.280 ;
        RECT 71.490 3.555 73.870 4.280 ;
        RECT 74.710 3.555 77.090 4.280 ;
        RECT 77.930 3.555 80.310 4.280 ;
        RECT 81.150 3.555 83.530 4.280 ;
        RECT 84.370 3.555 86.750 4.280 ;
        RECT 87.590 3.555 89.970 4.280 ;
        RECT 90.810 3.555 93.190 4.280 ;
        RECT 94.030 3.555 96.410 4.280 ;
        RECT 97.250 3.555 99.630 4.280 ;
        RECT 100.470 3.555 102.850 4.280 ;
        RECT 103.690 3.555 106.070 4.280 ;
        RECT 106.910 3.555 109.290 4.280 ;
        RECT 110.130 3.555 112.510 4.280 ;
        RECT 113.350 3.555 118.950 4.280 ;
        RECT 119.790 3.555 122.170 4.280 ;
        RECT 123.010 3.555 125.390 4.280 ;
        RECT 126.230 3.555 128.610 4.280 ;
        RECT 129.450 3.555 131.830 4.280 ;
        RECT 132.670 3.555 135.050 4.280 ;
        RECT 135.890 3.555 138.270 4.280 ;
        RECT 139.110 3.555 141.490 4.280 ;
        RECT 142.330 3.555 144.710 4.280 ;
        RECT 145.550 3.555 147.930 4.280 ;
        RECT 148.770 3.555 151.150 4.280 ;
        RECT 151.990 3.555 154.370 4.280 ;
        RECT 155.210 3.555 157.590 4.280 ;
        RECT 158.430 3.555 160.810 4.280 ;
        RECT 161.650 3.555 164.030 4.280 ;
        RECT 164.870 3.555 167.250 4.280 ;
        RECT 168.090 3.555 170.470 4.280 ;
      LAYER met3 ;
        RECT 4.400 179.840 169.370 180.705 ;
        RECT 4.000 177.840 169.770 179.840 ;
        RECT 4.400 176.440 169.370 177.840 ;
        RECT 4.000 174.440 169.770 176.440 ;
        RECT 4.400 173.040 169.370 174.440 ;
        RECT 4.000 171.040 169.770 173.040 ;
        RECT 4.400 169.640 169.370 171.040 ;
        RECT 4.000 167.640 169.770 169.640 ;
        RECT 4.400 166.240 169.370 167.640 ;
        RECT 4.000 164.240 169.770 166.240 ;
        RECT 4.400 162.840 169.370 164.240 ;
        RECT 4.000 160.840 169.770 162.840 ;
        RECT 4.400 159.440 169.370 160.840 ;
        RECT 4.000 157.440 169.770 159.440 ;
        RECT 4.400 156.040 169.370 157.440 ;
        RECT 4.000 154.040 169.770 156.040 ;
        RECT 4.400 152.640 169.370 154.040 ;
        RECT 4.000 150.640 169.770 152.640 ;
        RECT 4.400 149.240 169.370 150.640 ;
        RECT 4.000 147.240 169.770 149.240 ;
        RECT 4.400 145.840 169.370 147.240 ;
        RECT 4.000 143.840 169.770 145.840 ;
        RECT 4.400 142.440 169.370 143.840 ;
        RECT 4.000 140.440 169.770 142.440 ;
        RECT 4.400 139.040 169.370 140.440 ;
        RECT 4.000 137.040 169.770 139.040 ;
        RECT 4.400 135.640 169.370 137.040 ;
        RECT 4.000 133.640 169.770 135.640 ;
        RECT 4.400 132.240 169.370 133.640 ;
        RECT 4.000 130.240 169.770 132.240 ;
        RECT 4.400 128.840 169.370 130.240 ;
        RECT 4.000 126.840 169.770 128.840 ;
        RECT 4.400 125.440 169.370 126.840 ;
        RECT 4.000 120.040 169.770 125.440 ;
        RECT 4.400 118.640 169.370 120.040 ;
        RECT 4.000 116.640 169.770 118.640 ;
        RECT 4.400 115.240 169.370 116.640 ;
        RECT 4.000 113.240 169.770 115.240 ;
        RECT 4.400 111.840 169.370 113.240 ;
        RECT 4.000 109.840 169.770 111.840 ;
        RECT 4.400 108.440 169.370 109.840 ;
        RECT 4.000 106.440 169.770 108.440 ;
        RECT 4.400 105.040 169.370 106.440 ;
        RECT 4.000 103.040 169.770 105.040 ;
        RECT 4.400 101.640 169.370 103.040 ;
        RECT 4.000 99.640 169.770 101.640 ;
        RECT 4.400 98.240 169.370 99.640 ;
        RECT 4.000 96.240 169.770 98.240 ;
        RECT 4.400 94.840 169.370 96.240 ;
        RECT 4.000 92.840 169.770 94.840 ;
        RECT 4.400 91.440 169.370 92.840 ;
        RECT 4.000 89.440 169.770 91.440 ;
        RECT 4.400 88.040 169.370 89.440 ;
        RECT 4.000 86.040 169.770 88.040 ;
        RECT 4.400 84.640 169.370 86.040 ;
        RECT 4.000 82.640 169.770 84.640 ;
        RECT 4.400 81.240 169.370 82.640 ;
        RECT 4.000 79.240 169.770 81.240 ;
        RECT 4.400 77.840 169.370 79.240 ;
        RECT 4.000 75.840 169.770 77.840 ;
        RECT 4.400 74.440 169.370 75.840 ;
        RECT 4.000 72.440 169.770 74.440 ;
        RECT 4.400 71.040 169.370 72.440 ;
        RECT 4.000 69.040 169.770 71.040 ;
        RECT 4.400 67.640 169.370 69.040 ;
        RECT 4.000 65.640 169.770 67.640 ;
        RECT 4.400 64.240 169.370 65.640 ;
        RECT 4.000 58.840 169.770 64.240 ;
        RECT 4.400 57.440 169.370 58.840 ;
        RECT 4.000 55.440 169.770 57.440 ;
        RECT 4.400 54.040 169.370 55.440 ;
        RECT 4.000 52.040 169.770 54.040 ;
        RECT 4.400 50.640 169.370 52.040 ;
        RECT 4.000 48.640 169.770 50.640 ;
        RECT 4.400 47.240 169.370 48.640 ;
        RECT 4.000 45.240 169.770 47.240 ;
        RECT 4.400 43.840 169.370 45.240 ;
        RECT 4.000 41.840 169.770 43.840 ;
        RECT 4.400 40.440 169.370 41.840 ;
        RECT 4.000 38.440 169.770 40.440 ;
        RECT 4.400 37.040 169.370 38.440 ;
        RECT 4.000 35.040 169.770 37.040 ;
        RECT 4.400 33.640 169.370 35.040 ;
        RECT 4.000 31.640 169.770 33.640 ;
        RECT 4.400 30.240 169.370 31.640 ;
        RECT 4.000 28.240 169.770 30.240 ;
        RECT 4.400 26.840 169.370 28.240 ;
        RECT 4.000 24.840 169.770 26.840 ;
        RECT 4.400 23.440 169.370 24.840 ;
        RECT 4.000 21.440 169.770 23.440 ;
        RECT 4.400 20.040 169.370 21.440 ;
        RECT 4.000 18.040 169.770 20.040 ;
        RECT 4.400 16.640 169.370 18.040 ;
        RECT 4.000 14.640 169.770 16.640 ;
        RECT 4.400 13.240 169.370 14.640 ;
        RECT 4.000 11.240 169.770 13.240 ;
        RECT 4.400 9.840 169.370 11.240 ;
        RECT 4.000 7.840 169.770 9.840 ;
        RECT 4.400 6.440 169.370 7.840 ;
        RECT 4.000 4.440 169.770 6.440 ;
        RECT 4.400 3.575 169.370 4.440 ;
      LAYER met4 ;
        RECT 60.850 10.640 85.510 171.600 ;
        RECT 87.910 10.640 112.575 171.600 ;
        RECT 114.975 10.640 139.635 171.600 ;
        RECT 142.035 10.640 163.465 171.600 ;
      LAYER met5 ;
        RECT 5.520 120.025 167.900 141.975 ;
        RECT 5.520 93.280 167.900 115.225 ;
        RECT 5.520 66.535 167.900 88.480 ;
  END
END shiftregister
END LIBRARY

